VERSION 5.7 ;
  NOWIREEXTENSIONATPIN ON ;
  DIVIDERCHAR "/" ;
  BUSBITCHARS "[]" ;
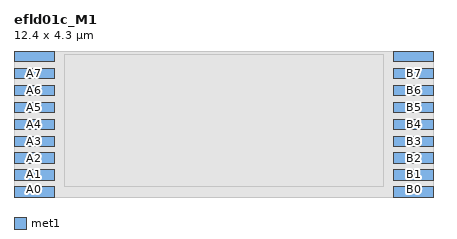
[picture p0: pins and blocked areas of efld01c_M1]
MACRO efld01c_M1
  CLASS BLOCK ;
  FOREIGN efld01c_M1 ;
  ORIGIN 0.000 0.000 ;
  SIZE 12.400 BY 4.300 ;
  PIN A0
    PORT
      LAYER met1 ;
        RECT 0.000 0.000 1.200 0.300 ;
    END
  END A0
  PIN A1
    PORT
      LAYER met1 ;
        RECT 0.000 0.500 1.200 0.800 ;
    END
  END A1
  PIN A2
    PORT
      LAYER met1 ;
        RECT 0.000 1.000 1.200 1.300 ;
    END
  END A2
  PIN A3
    PORT
      LAYER met1 ;
        RECT 0.000 1.500 1.200 1.800 ;
    END
  END A3
  PIN A4
    PORT
      LAYER met1 ;
        RECT 0.000 2.000 1.200 2.300 ;
    END
  END A4
  PIN A5
    PORT
      LAYER met1 ;
        RECT 0.000 2.500 1.200 2.800 ;
    END
  END A5
  PIN A6
    PORT
      LAYER met1 ;
        RECT 0.000 3.000 1.200 3.300 ;
    END
  END A6
  PIN A7
    PORT
      LAYER met1 ;
        RECT 0.000 3.500 1.200 3.800 ;
    END
  END A7
  PIN A8
    PORT
      LAYER met1 ;
        RECT 0.000 4.000 1.200 4.300 ;
    END
  END A8
  PIN B0
    PORT
      LAYER met1 ;
        RECT 11.200 0.000 12.400 0.300 ;
    END
  END B0
  PIN B1
    PORT
      LAYER met1 ;
        RECT 11.200 0.500 12.400 0.800 ;
    END
  END B1
  PIN B2
    PORT
      LAYER met1 ;
        RECT 11.200 1.000 12.400 1.300 ;
    END
  END B2
  PIN B3
    PORT
      LAYER met1 ;
        RECT 11.200 1.500 12.400 1.800 ;
    END
  END B3
  PIN B4
    PORT
      LAYER met1 ;
        RECT 11.200 2.000 12.400 2.300 ;
    END
  END B4
  PIN B5
    PORT
      LAYER met1 ;
        RECT 11.200 2.500 12.400 2.800 ;
    END
  END B5
  PIN B6
    PORT
      LAYER met1 ;
        RECT 11.200 3.000 12.400 3.300 ;
    END
  END B6
  PIN B7
    PORT
      LAYER met1 ;
        RECT 11.200 3.500 12.400 3.800 ;
    END
  END B7
  PIN B8
    PORT
      LAYER met1 ;
        RECT 11.200 4.000 12.400 4.300 ;
    END
  END B8
  OBS
      LAYER met1 ;
        RECT 0.000 0.300 1.200 0.500 ;
        RECT 0.000 0.800 1.200 1.000 ;
        RECT 0.000 1.300 1.200 1.500 ;
        RECT 0.000 1.800 1.200 2.000 ;
        RECT 0.000 2.300 1.200 2.500 ;
        RECT 0.000 2.800 1.200 3.000 ;
        RECT 0.000 3.300 1.200 3.500 ;
        RECT 0.000 3.800 1.200 4.000 ;
        RECT 11.200 0.300 12.400 0.500 ;
        RECT 11.200 0.800 12.400 1.000 ;
        RECT 11.200 1.300 12.400 1.500 ;
        RECT 11.200 1.800 12.400 2.000 ;
        RECT 11.200 2.300 12.400 2.500 ;
        RECT 11.200 2.800 12.400 3.000 ;
        RECT 11.200 3.300 12.400 3.500 ;
        RECT 11.200 3.800 12.400 4.000 ;
      LAYER li1 ;
        RECT 0.000 0.000 12.400 4.300 ;
      LAYER met1 ;
        RECT 1.480 0.300 10.920 4.220 ;
  END
END efld01c_M1
END LIBRARY

